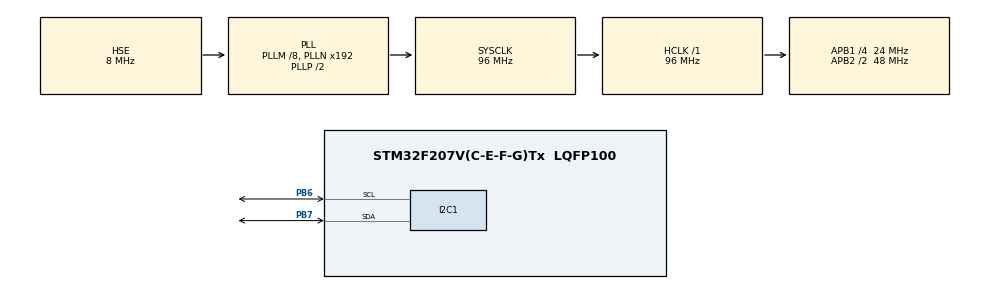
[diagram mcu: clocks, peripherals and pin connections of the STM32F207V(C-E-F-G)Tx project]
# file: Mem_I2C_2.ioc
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Mcu.Family=STM32F2
Mcu.Name=STM32F207V(C-E-F-G)Tx
Mcu.Package=LQFP100
NVIC.PriorityGroup=NVIC_PRIORITYGROUP_4
PA13.Mode=Serial_Wire
PA13.Signal=SYS_JTMS-SWDIO
PA14.Mode=Serial_Wire
PA14.Signal=SYS_JTCK-SWCLK
PB6.Mode=I2C
PB6.Signal=I2C1_SCL
PB7.Mode=I2C
PB7.Signal=I2C1_SDA
PC14-OSC32_IN.Mode=LSE-External-Oscillator
PC14-OSC32_IN.Signal=RCC_OSC32_IN
PC15-OSC32_OUT.Mode=LSE-External-Oscillator
PC15-OSC32_OUT.Signal=RCC_OSC32_OUT
PH0-OSC_IN.Mode=HSE-External-Oscillator
PH0-OSC_IN.Signal=RCC_OSC_IN
PH1-OSC_OUT.Mode=HSE-External-Oscillator
PH1-OSC_OUT.Signal=RCC_OSC_OUT
ProjectManager.HeapSize=0x200
ProjectManager.StackSize=0x400
ProjectManager.TargetToolchain=EWARM V8.32
RCC.48MHZClocksFreq_Value=48000000
RCC.AHBFreq_Value=96000000
RCC.APB1CLKDivider=RCC_HCLK_DIV4
RCC.APB1Freq_Value=24000000
RCC.APB1TimFreq_Value=48000000
RCC.APB2CLKDivider=RCC_HCLK_DIV2
RCC.APB2Freq_Value=48000000
RCC.APB2TimFreq_Value=96000000
RCC.CortexFreq_Value=12000000
RCC.Cortex_Div=SYSTICK_CLKSOURCE_HCLK_DIV8
RCC.HCLKFreq_Value=96000000
RCC.HSE_VALUE=8000000
RCC.HSI_VALUE=16000000
RCC.PLLM=8
RCC.PLLSourceVirtual=RCC_PLLSOURCE_HSE
RCC.SYSCLKFreq_VALUE=96000000
RCC.SYSCLKSource=RCC_SYSCLKSOURCE_PLLCLK
RCC.VCOOutputFreq_Value=192000000
board=custom

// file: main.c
/* USER CODE BEGIN Header */
/**
  ******************************************************************************
  * @file           : main.c
  * @brief          : Main program body
  ******************************************************************************
  * @attention
  *
  * Copyright (c) 2022 STMicroelectronics.
  * All rights reserved.
  *
  * This software is licensed under terms that can be found in the LICENSE file
  * in the root directory of this software component.
  * If no LICENSE file comes with this software, it is provided AS-IS.
  *
  ******************************************************************************
  */
/* USER CODE END Header */
#include "main.h"
#include "string.h"

I2C_HandleTypeDef hi2c1;

/* USER CODE BEGIN PV */
uint8_t dataWrite[] = "Arcu arcu id mollis tortor, sed vitae velit velit habitasse hac molestie interdum risus mattis sed odio. Nulla odio. Cursus platea est. Dic";
//uint8_t dataWrite[] = "When the days are cold, and the cards are fold, and the saints we see, are all made of gold";
//uint8_t dataWrite[] = "the first word";
//uint8_t dataWrite1[] = "1111111";
uint8_t dataRead[sizeof(dataWrite)];
//uint8_t dataRead1[sizeof(dataWrite1)];

#define I2C1_DEVICE_ADDRESS      0x50   // 1010 _ A0 = A1 = A2 = 0
#define MEMORY_ADDRESS           0
/* USER CODE END PV */

void SystemClock_Config(void);
static void MX_GPIO_Init(void);
static void MX_I2C1_Init(void);

int main(void)
{

  /* MCU Configuration--------------------------------------------------------*/

  /* Reset of all peripherals, Initializes the Flash interface and the Systick. */
  HAL_Init();

  /* Configure the system clock */
  SystemClock_Config();

  /* Initialize all configured peripherals */
  MX_GPIO_Init();
  MX_I2C1_Init();

  /* Infinite loop */
  while (1)
  {

                Eeprom_Write(&hi2c1, I2C1_DEVICE_ADDRESS << 1, MEMORY_ADDRESS, dataWrite, sizeof(dataWrite));
                Eeprom_Read(&hi2c1, I2C1_DEVICE_ADDRESS << 1, MEMORY_ADDRESS, dataRead, sizeof(dataRead));

                /*HAL_StatusTypeDef aaa = HAL_I2C_Mem_Write(&hi2c1, (I2C1_DEVICE_ADDRESS<<1), 0x00, 1, dataWrite, sizeof(dataWrite), 1000);   //write to memory address 0x40

                HAL_Delay(10); //memory write delay

                aaa = HAL_I2C_Mem_Read(&hi2c1, (I2C1_DEVICE_ADDRESS<<1), 0x00, 1 , dataRead, sizeof(dataRead), 10);

                HAL_StatusTypeDef aa = HAL_I2C_Mem_Write(&hi2c1, (I2C1_DEVICE_ADDRESS<<1), 0x10, 1, dataWrite1, sizeof(dataWrite1), 10);   //write to memory address 0x40

                HAL_Delay(10); //memory write delay

                HAL_I2C_Mem_Read(&hi2c1, (I2C1_DEVICE_ADDRESS<<1), 0x10, 1 , dataRead1, sizeof(dataRead1), 10);   */

               /* if (memcmp(dataWrite, dataRead, (sizeof(dataWrite))) == 0)
                {
                     HAL_Delay(100);
                     HAL_GPIO_WritePin(LED_GPIO_Port, LED_Pin, GPIO_PIN_SET); //GREEN LED ON
                }

                else
                {
                     HAL_Delay(100);
                     HAL_GPIO_WritePin(LED_B_GPIO_Port, LED_B_Pin, GPIO_PIN_SET); // BLUE LED ON
                }*/

  }
}

void SystemClock_Config(void)
{
  RCC_OscInitTypeDef RCC_OscInitStruct = {0};
  RCC_ClkInitTypeDef RCC_ClkInitStruct = {0};

  /** Initializes the RCC Oscillators according to the specified parameters
  * in the RCC_OscInitTypeDef structure.
  */
  RCC_OscInitStruct.OscillatorType = RCC_OSCILLATORTYPE_HSE;
  RCC_OscInitStruct.HSEState = RCC_HSE_ON;
  RCC_OscInitStruct.PLL.PLLState = RCC_PLL_ON;
  RCC_OscInitStruct.PLL.PLLSource = RCC_PLLSOURCE_HSE;
  RCC_OscInitStruct.PLL.PLLM = 8;
  RCC_OscInitStruct.PLL.PLLN = 192;
  RCC_OscInitStruct.PLL.PLLP = RCC_PLLP_DIV2;
  RCC_OscInitStruct.PLL.PLLQ = 4;
  if (HAL_RCC_OscConfig(&RCC_OscInitStruct) != HAL_OK)
  {
    Error_Handler();
  }
  /** Initializes the CPU, AHB and APB buses clocks
  */
  RCC_ClkInitStruct.ClockType = RCC_CLOCKTYPE_HCLK|RCC_CLOCKTYPE_SYSCLK
                              |RCC_CLOCKTYPE_PCLK1|RCC_CLOCKTYPE_PCLK2;
  RCC_ClkInitStruct.SYSCLKSource = RCC_SYSCLKSOURCE_PLLCLK;
  RCC_ClkInitStruct.AHBCLKDivider = RCC_SYSCLK_DIV1;
  RCC_ClkInitStruct.APB1CLKDivider = RCC_HCLK_DIV4;
  RCC_ClkInitStruct.APB2CLKDivider = RCC_HCLK_DIV2;

  if (HAL_RCC_ClockConfig(&RCC_ClkInitStruct, FLASH_LATENCY_3) != HAL_OK)
  {
    Error_Handler();
  }
}

static void MX_I2C1_Init(void)
{

  hi2c1.Instance = I2C1;
  hi2c1.Init.ClockSpeed = 100000;
  hi2c1.Init.DutyCycle = I2C_DUTYCYCLE_2;
  hi2c1.Init.OwnAddress1 = 0;
  hi2c1.Init.AddressingMode = I2C_ADDRESSINGMODE_7BIT;
  hi2c1.Init.DualAddressMode = I2C_DUALADDRESS_DISABLE;
  hi2c1.Init.OwnAddress2 = 0;
  hi2c1.Init.GeneralCallMode = I2C_GENERALCALL_DISABLE;
  hi2c1.Init.NoStretchMode = I2C_NOSTRETCH_DISABLE;
  if (HAL_I2C_Init(&hi2c1) != HAL_OK)
  {
    Error_Handler();
  }

}

static void MX_GPIO_Init(void)
{
  GPIO_InitTypeDef GPIO_InitStruct = {0};

  /* GPIO Ports Clock Enable */
  __HAL_RCC_GPIOC_CLK_ENABLE();
  __HAL_RCC_GPIOH_CLK_ENABLE();
  __HAL_RCC_GPIOE_CLK_ENABLE();
  __HAL_RCC_GPIOA_CLK_ENABLE();
  __HAL_RCC_GPIOB_CLK_ENABLE();

  /*Configure GPIO pin Output Level */
  HAL_GPIO_WritePin(GPIOE, LED_Pin|LED_B_Pin, GPIO_PIN_RESET);

  /*Configure GPIO pins : LED_Pin LED_B_Pin */
  GPIO_InitStruct.Pin = LED_Pin|LED_B_Pin;
  GPIO_InitStruct.Mode = GPIO_MODE_OUTPUT_PP;
  GPIO_InitStruct.Pull = GPIO_NOPULL;
  GPIO_InitStruct.Speed = GPIO_SPEED_FREQ_LOW;
  HAL_GPIO_Init(GPIOE, &GPIO_InitStruct);

}

void Error_Handler(void)
{
  __disable_irq();
  while (1)
  {
  }
}
